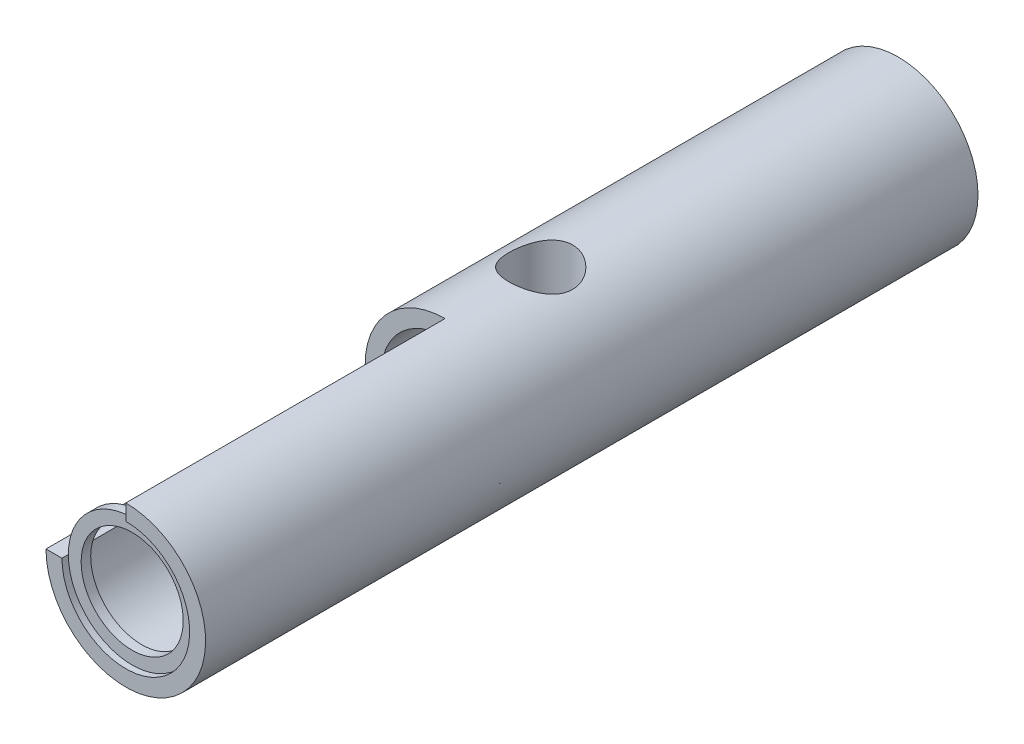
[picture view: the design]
ISO-10303-21;
HEADER;
FILE_DESCRIPTION(('STEP AP214'),'2;1');
FILE_NAME('part.step','',(''),(''),'','','');
FILE_SCHEMA(('AUTOMOTIVE_DESIGN { 1 0 10303 214 1 1 1 1 }'));
ENDSEC;
DATA;
#1=APPLICATION_CONTEXT('core data for automotive mechanical design processes');
#2=APPLICATION_PROTOCOL_DEFINITION('international standard','automotive_design',2000,#1);
#3=PRODUCT_CONTEXT('',#1,'mechanical');
#4=PRODUCT('Part','Part','',(#3));
#5=PRODUCT_RELATED_PRODUCT_CATEGORY('part','',(#4));
#6=PRODUCT_DEFINITION_FORMATION('','',#4);
#7=PRODUCT_DEFINITION_CONTEXT('part definition',#1,'design');
#8=PRODUCT_DEFINITION('design','',#6,#7);
#9=PRODUCT_DEFINITION_SHAPE('','',#8);
#10=(LENGTH_UNIT() NAMED_UNIT(*) SI_UNIT(.MILLI.,.METRE.));
#11=(NAMED_UNIT(*) PLANE_ANGLE_UNIT() SI_UNIT($,.RADIAN.));
#12=(NAMED_UNIT(*) SI_UNIT($,.STERADIAN.) SOLID_ANGLE_UNIT());
#13=UNCERTAINTY_MEASURE_WITH_UNIT(LENGTH_MEASURE(1.E-05),#10,'distance_accuracy_value','');
#14=(GEOMETRIC_REPRESENTATION_CONTEXT(3) GLOBAL_UNCERTAINTY_ASSIGNED_CONTEXT((#13)) GLOBAL_UNIT_ASSIGNED_CONTEXT((#10,
#11,#12)) REPRESENTATION_CONTEXT('',''));
#15=CARTESIAN_POINT('',(0.,0.,0.));
#16=DIRECTION('',(0.,0.,1.));
#17=DIRECTION('',(1.,0.,0.));
#18=AXIS2_PLACEMENT_3D('',#15,#16,#17);
#19=CARTESIAN_POINT('',(0.,0.,63.));
#20=DIRECTION('',(0.,0.,1.));
#21=DIRECTION('',(1.,0.,0.));
#22=AXIS2_PLACEMENT_3D('',#19,#20,#21);
#23=CYLINDRICAL_SURFACE('',#22,10.);
#24=DIRECTION('',(0.,0.,1.));
#25=VECTOR('',#24,1.);
#26=CARTESIAN_POINT('',(0.,10.,63.));
#27=LINE('',#26,#25);
#28=CARTESIAN_POINT('',(0.,10.,121.));
#29=VERTEX_POINT('',#28);
#30=CARTESIAN_POINT('',(0.,10.,120.));
#31=VERTEX_POINT('',#30);
#32=EDGE_CURVE('E107',#29,#31,#27,.F.);
#33=ORIENTED_EDGE('',*,*,#32,.T.);
#34=CARTESIAN_POINT('',(0.,0.,120.));
#35=DIRECTION('',(0.,0.,-1.));
#36=DIRECTION('',(-1.,0.,0.));
#37=AXIS2_PLACEMENT_3D('',#34,#35,#36);
#38=CIRCLE('',#37,10.);
#39=CARTESIAN_POINT('',(-10.,0.,120.));
#40=VERTEX_POINT('',#39);
#41=EDGE_CURVE('E106',#31,#40,#38,.T.);
#42=ORIENTED_EDGE('',*,*,#41,.T.);
#43=DIRECTION('',(0.,0.,1.));
#44=VECTOR('',#43,1.);
#45=CARTESIAN_POINT('',(-10.,0.,63.));
#46=LINE('',#45,#44);
#47=CARTESIAN_POINT('',(-10.,0.,121.));
#48=VERTEX_POINT('',#47);
#49=EDGE_CURVE('E51',#40,#48,#46,.T.);
#50=ORIENTED_EDGE('',*,*,#49,.T.);
#51=CARTESIAN_POINT('',(0.,0.,121.));
#52=DIRECTION('',(0.,0.,1.));
#53=DIRECTION('',(1.,0.,0.));
#54=AXIS2_PLACEMENT_3D('',#51,#52,#53);
#55=CIRCLE('',#54,10.);
#56=EDGE_CURVE('E212',#48,#29,#55,.T.);
#57=ORIENTED_EDGE('',*,*,#56,.T.);
#58=EDGE_LOOP('',(#33,#42,#50,#57));
#59=FACE_BOUND('',#58,.T.);
#60=ADVANCED_FACE('F41',(#59),#23,.F.);
#61=CARTESIAN_POINT('',(0.,0.,0.));
#62=DIRECTION('',(0.,0.,1.));
#63=DIRECTION('',(1.,0.,0.));
#64=AXIS2_PLACEMENT_3D('',#61,#62,#63);
#65=CYLINDRICAL_SURFACE('',#64,4.);
#66=CARTESIAN_POINT('',(4.,0.,53.));
#67=CARTESIAN_POINT('',(3.99999906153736,0.0751127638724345,52.9999978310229));
#68=CARTESIAN_POINT('',(3.9978772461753,0.150254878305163,52.9971622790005));
#69=CARTESIAN_POINT('',(3.9894472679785,0.2999085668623,52.9859741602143));
#70=CARTESIAN_POINT('',(3.98313625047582,0.374419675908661,52.9776178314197));
#71=CARTESIAN_POINT('',(3.95807727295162,0.596479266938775,52.9447707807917));
#72=CARTESIAN_POINT('',(3.93320424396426,0.742244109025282,52.9125044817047));
#73=CARTESIAN_POINT('',(3.85777127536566,1.0752679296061,52.8184478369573));
#74=CARTESIAN_POINT('',(3.80127986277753,1.25928076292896,52.7502867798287));
#75=CARTESIAN_POINT('',(3.66572012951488,1.61194054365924,52.5981035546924));
#76=CARTESIAN_POINT('',(3.58658817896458,1.78054239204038,52.5140369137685));
#77=CARTESIAN_POINT('',(3.43637278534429,2.05110258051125,52.3670054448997));
#78=CARTESIAN_POINT('',(3.37076459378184,2.15717257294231,52.305856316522));
#79=CARTESIAN_POINT('',(3.23028207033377,2.3623609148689,52.1824073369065));
#80=CARTESIAN_POINT('',(3.15540441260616,2.4614767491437,52.1201070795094));
#81=CARTESIAN_POINT('',(2.99663184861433,2.6524698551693,51.9962104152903));
#82=CARTESIAN_POINT('',(2.91274636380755,2.74435451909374,51.9346133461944));
#83=CARTESIAN_POINT('',(2.73598294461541,2.92061301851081,51.8136076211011));
#84=CARTESIAN_POINT('',(2.64310382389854,3.00498586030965,51.7541992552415));
#85=CARTESIAN_POINT('',(2.38958702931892,3.21416413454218,51.6042350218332));
#86=CARTESIAN_POINT('',(2.22188522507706,3.33264039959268,51.5165192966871));
#87=CARTESIAN_POINT('',(1.86487183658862,3.54474406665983,51.3566840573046));
#88=CARTESIAN_POINT('',(1.67559449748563,3.63841008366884,51.2845403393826));
#89=CARTESIAN_POINT('',(1.31063780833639,3.7834234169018,51.1716897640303));
#90=CARTESIAN_POINT('',(1.13770814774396,3.83916445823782,51.1277859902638));
#91=CARTESIAN_POINT('',(0.782375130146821,3.92699806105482,51.0582810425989));
#92=CARTESIAN_POINT('',(0.599977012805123,3.95910355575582,51.032669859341));
#93=CARTESIAN_POINT('',(0.230096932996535,3.99771600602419,51.0018408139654));
#94=CARTESIAN_POINT('',(0.042599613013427,4.00413433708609,50.9966935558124));
#95=CARTESIAN_POINT('',(-0.33083280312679,3.99067157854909,51.0074612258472));
#96=CARTESIAN_POINT('',(-0.516767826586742,3.97078927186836,51.0233771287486));
#97=CARTESIAN_POINT('',(-0.871367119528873,3.90786401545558,51.0734326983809));
#98=CARTESIAN_POINT('',(-1.04042037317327,3.86614236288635,51.1065319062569));
#99=CARTESIAN_POINT('',(-1.36834372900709,3.76260953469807,51.1879101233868));
#100=CARTESIAN_POINT('',(-1.5272112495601,3.70079328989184,51.2361929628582));
#101=CARTESIAN_POINT('',(-1.84705463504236,3.55279860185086,51.3502755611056));
#102=CARTESIAN_POINT('',(-2.00675938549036,3.46484696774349,51.417314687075));
#103=CARTESIAN_POINT('',(-2.30941782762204,3.27092428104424,51.5621191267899));
#104=CARTESIAN_POINT('',(-2.4523620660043,3.16494314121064,51.6398904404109));
#105=CARTESIAN_POINT('',(-2.7485304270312,2.91387626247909,51.81892978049));
#106=CARTESIAN_POINT('',(-2.89780217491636,2.76523277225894,51.9217371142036));
#107=CARTESIAN_POINT('',(-3.17076769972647,2.44748819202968,52.1301524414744));
#108=CARTESIAN_POINT('',(-3.29442988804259,2.27836224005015,52.2357637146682));
#109=CARTESIAN_POINT('',(-3.50457057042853,1.9375596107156,52.4311736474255));
#110=CARTESIAN_POINT('',(-3.59348348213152,1.76769812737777,52.5215155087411));
#111=CARTESIAN_POINT('',(-3.74778213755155,1.41126705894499,52.688357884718));
#112=CARTESIAN_POINT('',(-3.81321930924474,1.22473512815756,52.7648884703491));
#113=CARTESIAN_POINT('',(-3.90124400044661,0.894416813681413,52.8721238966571));
#114=CARTESIAN_POINT('',(-3.93080589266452,0.754774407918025,52.9096879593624));
#115=CARTESIAN_POINT('',(-3.97493954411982,0.469639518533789,52.9666539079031));
#116=CARTESIAN_POINT('',(-3.98954472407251,0.324160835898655,52.9860962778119));
#117=CARTESIAN_POINT('',(-4.00259995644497,0.0302735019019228,53.0034441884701));
#118=CARTESIAN_POINT('',(-4.00095637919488,-0.118147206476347,53.0012249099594));
#119=CARTESIAN_POINT('',(-3.98145195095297,-0.41209561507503,52.9753908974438));
#120=CARTESIAN_POINT('',(-3.96356821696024,-0.557618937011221,52.9517459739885));
#121=CARTESIAN_POINT('',(-3.90662980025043,-0.87812188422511,52.8789697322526));
#122=CARTESIAN_POINT('',(-3.86334682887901,-1.05117767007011,52.8248851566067));
#123=CARTESIAN_POINT('',(-3.7568227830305,-1.38460065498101,52.6995442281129));
#124=CARTESIAN_POINT('',(-3.69352220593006,-1.54492821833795,52.6282368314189));
#125=CARTESIAN_POINT('',(-3.56873529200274,-1.81092552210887,52.4971442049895));
#126=CARTESIAN_POINT('',(-3.5113936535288,-1.91964530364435,52.4394629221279));
#127=CARTESIAN_POINT('',(-3.38766369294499,-2.13041737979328,52.3215449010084));
#128=CARTESIAN_POINT('',(-3.32127165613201,-2.23246691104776,52.2613071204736));
#129=CARTESIAN_POINT('',(-3.17963685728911,-2.42995611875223,52.140127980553));
#130=CARTESIAN_POINT('',(-3.10438543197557,-2.52538917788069,52.0791859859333));
#131=CARTESIAN_POINT('',(-2.9452042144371,-2.70934721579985,51.9582475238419));
#132=CARTESIAN_POINT('',(-2.86127578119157,-2.79787327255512,51.8982509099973));
#133=CARTESIAN_POINT('',(-2.68353213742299,-2.96885093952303,51.779783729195));
#134=CARTESIAN_POINT('',(-2.5895923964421,-3.05119722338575,51.7213473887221));
#135=CARTESIAN_POINT('',(-2.39294409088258,-3.2077427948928,51.6083394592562));
#136=CARTESIAN_POINT('',(-2.29023415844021,-3.28194080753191,51.5537684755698));
#137=CARTESIAN_POINT('',(-2.07659269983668,-3.42110502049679,51.4500754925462));
#138=CARTESIAN_POINT('',(-1.96568453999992,-3.48609602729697,51.4009389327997));
#139=CARTESIAN_POINT('',(-1.73599312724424,-3.6059828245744,51.3094118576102));
#140=CARTESIAN_POINT('',(-1.61721438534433,-3.66088433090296,51.2670175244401));
#141=CARTESIAN_POINT('',(-1.32913962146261,-3.77693416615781,51.1767794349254));
#142=CARTESIAN_POINT('',(-1.15683679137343,-3.83342216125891,51.1323129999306));
#143=CARTESIAN_POINT('',(-0.802710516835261,-3.92287685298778,51.0615575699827));
#144=CARTESIAN_POINT('',(-0.620894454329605,-3.95586150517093,51.0352546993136));
#145=CARTESIAN_POINT('',(-0.251928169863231,-3.99638225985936,51.0029090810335));
#146=CARTESIAN_POINT('',(-0.0647609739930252,-4.00382550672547,50.9969402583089));
#147=CARTESIAN_POINT('',(0.308260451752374,-3.99246788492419,51.0060247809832));
#148=CARTESIAN_POINT('',(0.494114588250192,-3.97366516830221,51.0210796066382));
#149=CARTESIAN_POINT('',(0.848969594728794,-3.91279269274,51.0695200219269));
#150=CARTESIAN_POINT('',(1.01834018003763,-3.87202131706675,51.1018819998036));
#151=CARTESIAN_POINT('',(1.34704122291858,-3.7702931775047,51.1818959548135));
#152=CARTESIAN_POINT('',(1.50636906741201,-3.70933118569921,51.2295518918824));
#153=CARTESIAN_POINT('',(1.82676698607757,-3.56325105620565,51.3422757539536));
#154=CARTESIAN_POINT('',(1.98661951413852,-3.47641294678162,51.4085512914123));
#155=CARTESIAN_POINT('',(2.28972858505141,-3.2847146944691,51.5519328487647));
#156=CARTESIAN_POINT('',(2.43297624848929,-3.17984498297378,51.6290446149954));
#157=CARTESIAN_POINT('',(2.72976152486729,-2.931410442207,51.8066594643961));
#158=CARTESIAN_POINT('',(2.87940400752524,-2.78431890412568,51.9087197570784));
#159=CARTESIAN_POINT('',(3.15339914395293,-2.46975440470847,52.1159880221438));
#160=CARTESIAN_POINT('',(3.2777199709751,-2.30225621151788,52.2211997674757));
#161=CARTESIAN_POINT('',(3.43993958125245,-2.0435346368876,52.3707201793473));
#162=CARTESIAN_POINT('',(3.488247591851,-1.95998002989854,52.4172293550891));
#163=CARTESIAN_POINT('',(3.57912761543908,-1.78864740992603,52.5080121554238));
#164=CARTESIAN_POINT('',(3.62169886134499,-1.70086883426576,52.5522854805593));
#165=CARTESIAN_POINT('',(3.74029659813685,-1.43132131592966,52.6798301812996));
#166=CARTESIAN_POINT('',(3.80747088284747,-1.24292483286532,52.7580790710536));
#167=CARTESIAN_POINT('',(3.89828691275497,-0.907661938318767,52.8683954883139));
#168=CARTESIAN_POINT('',(3.92892882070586,-0.765010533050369,52.9072768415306));
#169=CARTESIAN_POINT('',(3.96316402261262,-0.546591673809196,52.9514490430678));
#170=CARTESIAN_POINT('',(3.97261660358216,-0.473140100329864,52.9638081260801));
#171=CARTESIAN_POINT('',(3.98745340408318,-0.325161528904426,52.983317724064));
#172=CARTESIAN_POINT('',(3.99284047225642,-0.250635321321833,52.9904718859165));
#173=CARTESIAN_POINT('',(3.99741959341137,-0.146618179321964,52.996562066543));
#174=CARTESIAN_POINT('',(3.99838660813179,-0.11732119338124,52.9978498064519));
#175=CARTESIAN_POINT('',(3.99967703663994,-0.058684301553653,52.9995692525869));
#176=CARTESIAN_POINT('',(4.00000036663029,-0.0293443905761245,53.0000008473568));
#177=CARTESIAN_POINT('',(4.,0.,53.));
#178=B_SPLINE_CURVE_WITH_KNOTS('',3,(#66,#67,#68,#69,#70,#71,#72,#73,#74,#75,#76,#77,#78,#79,
#80,#81,#82,#83,#84,#85,#86,#87,#88,#89,#90,#91,#92,#93,#94,#95,#96,#97,#98,#99,#100,#101,#102,
#103,#104,#105,#106,#107,#108,#109,#110,#111,#112,#113,#114,#115,#116,#117,#118,#119,#120,#121,
#122,#123,#124,#125,#126,#127,#128,#129,#130,#131,#132,#133,#134,#135,#136,#137,#138,#139,#140,
#141,#142,#143,#144,#145,#146,#147,#148,#149,#150,#151,#152,#153,#154,#155,#156,#157,#158,#159,
#160,#161,#162,#163,#164,#165,#166,#167,#168,#169,#170,#171,#172,#173,#174,#175,#176,#177),
.UNSPECIFIED.,.T.,.F.,(4,2,2,2,2,2,2,2,2,2,2,2,2,2,2,2,2,2,2,2,2,2,2,2,2,2,2,2,2,2,2,2,2,2,2,2,
2,2,2,2,2,2,2,2,2,2,2,2,2,2,2,2,2,2,2,4),(0.,0.225303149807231,0.450759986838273,
0.902589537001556,1.51190711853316,2.12295426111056,2.53921883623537,2.95563320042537,
3.37161619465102,3.78765413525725,4.45477512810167,5.12085162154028,5.67923095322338,
6.23730451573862,6.79730186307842,7.35732512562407,7.88682741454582,8.41646338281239,
8.99711927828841,9.57810111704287,10.2788135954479,10.9803852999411,11.6143729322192,
12.2469630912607,12.6881435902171,13.1283361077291,13.5710666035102,14.0144218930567,
14.5705602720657,15.1283675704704,15.5352238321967,15.942247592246,16.3496727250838,
16.7570341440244,17.1702378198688,17.5835060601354,17.9956387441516,18.4075372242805,
18.9651425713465,19.5223214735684,20.0815238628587,20.6407656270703,21.1700928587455,
21.6995572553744,22.2782911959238,22.8573331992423,23.5548944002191,24.2533270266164,
24.5745079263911,24.8957317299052,25.5365329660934,25.9876445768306,26.2126360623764,
26.4374697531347,26.5254777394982,26.6134971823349),.UNSPECIFIED.);
#179=CARTESIAN_POINT('',(4.,0.,53.));
#180=VERTEX_POINT('',#179);
#181=EDGE_CURVE('E182',#180,#180,#178,.T.);
#182=ORIENTED_EDGE('',*,*,#181,.T.);
#183=EDGE_LOOP('',(#182));
#184=FACE_BOUND('',#183,.T.);
#185=CARTESIAN_POINT('',(0.,0.,0.));
#186=DIRECTION('',(0.,0.,1.));
#187=DIRECTION('',(1.,0.,0.));
#188=AXIS2_PLACEMENT_3D('',#185,#186,#187);
#189=CIRCLE('',#188,4.);
#190=CARTESIAN_POINT('',(4.,0.,0.));
#191=VERTEX_POINT('',#190);
#192=EDGE_CURVE('E215',#191,#191,#189,.T.);
#193=ORIENTED_EDGE('',*,*,#192,.F.);
#194=EDGE_LOOP('',(#193));
#195=FACE_BOUND('',#194,.T.);
#196=ADVANCED_FACE('F230',(#184,#195),#65,.F.);
#197=CARTESIAN_POINT('',(0.,0.,121.));
#198=DIRECTION('',(0.,0.,-1.));
#199=DIRECTION('',(-1.,0.,0.));
#200=AXIS2_PLACEMENT_3D('',#197,#198,#199);
#201=CYLINDRICAL_SURFACE('',#200,12.5);
#202=CARTESIAN_POINT('',(0.,-12.5,59.));
#203=CARTESIAN_POINT('',(0.165963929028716,-12.4999970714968,58.9999949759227));
#204=CARTESIAN_POINT('',(0.331985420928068,-12.4966615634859,58.9861815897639));
#205=CARTESIAN_POINT('',(0.65928429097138,-12.4836783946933,58.9313672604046));
#206=CARTESIAN_POINT('',(0.820558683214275,-12.4740268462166,58.8903495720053));
#207=CARTESIAN_POINT('',(1.13358839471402,-12.4494823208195,58.7825076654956));
#208=CARTESIAN_POINT('',(1.28535442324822,-12.4345953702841,58.7157131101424));
#209=CARTESIAN_POINT('',(1.57552517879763,-12.4011725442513,58.5583145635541));
#210=CARTESIAN_POINT('',(1.71392971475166,-12.3826366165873,58.4677102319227));
#211=CARTESIAN_POINT('',(1.97609263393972,-12.3435386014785,58.2634358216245));
#212=CARTESIAN_POINT('',(2.0995595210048,-12.3229472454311,58.1493972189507));
#213=CARTESIAN_POINT('',(2.32581080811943,-12.2822574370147,57.9022811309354));
#214=CARTESIAN_POINT('',(2.42859304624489,-12.2621590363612,57.7692016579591));
#215=CARTESIAN_POINT('',(2.61189993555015,-12.224437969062,57.4855541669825));
#216=CARTESIAN_POINT('',(2.69210377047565,-12.2068525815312,57.3347734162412));
#217=CARTESIAN_POINT('',(2.82591582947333,-12.1765733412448,57.0213801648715));
#218=CARTESIAN_POINT('',(2.87952794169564,-12.1638787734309,56.8587693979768));
#219=CARTESIAN_POINT('',(2.95765058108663,-12.1451184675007,56.5295234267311));
#220=CARTESIAN_POINT('',(2.98268262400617,-12.1389341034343,56.3630188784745));
#221=CARTESIAN_POINT('',(3.00455808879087,-12.1335389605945,56.0280676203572));
#222=CARTESIAN_POINT('',(3.00140571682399,-12.1343271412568,55.8596212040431));
#223=CARTESIAN_POINT('',(2.96741912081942,-12.1426811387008,55.5295240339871));
#224=CARTESIAN_POINT('',(2.93720103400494,-12.1500960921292,55.3678054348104));
#225=CARTESIAN_POINT('',(2.85092141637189,-12.1706283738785,55.0518026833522));
#226=CARTESIAN_POINT('',(2.79485817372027,-12.1837460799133,54.8975190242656));
#227=CARTESIAN_POINT('',(2.65794121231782,-12.2143476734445,54.5990870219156));
#228=CARTESIAN_POINT('',(2.5768594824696,-12.2318714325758,54.4550475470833));
#229=CARTESIAN_POINT('',(2.39236688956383,-12.2692875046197,54.1823954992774));
#230=CARTESIAN_POINT('',(2.28895240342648,-12.2891802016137,54.0537854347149));
#231=CARTESIAN_POINT('',(2.05951493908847,-12.329732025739,53.8121064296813));
#232=CARTESIAN_POINT('',(1.93297064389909,-12.3503975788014,53.6995329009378));
#233=CARTESIAN_POINT('',(1.66255592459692,-12.3896951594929,53.4971152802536));
#234=CARTESIAN_POINT('',(1.51868504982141,-12.4083271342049,53.4072717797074));
#235=CARTESIAN_POINT('',(1.21702847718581,-12.4415394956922,53.2527027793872));
#236=CARTESIAN_POINT('',(1.05920278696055,-12.4561077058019,53.1880525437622));
#237=CARTESIAN_POINT('',(0.734497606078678,-12.4794620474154,53.0863349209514));
#238=CARTESIAN_POINT('',(0.567619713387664,-12.4882491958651,53.0492626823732));
#239=CARTESIAN_POINT('',(0.233787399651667,-12.4989027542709,53.004497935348));
#240=CARTESIAN_POINT('',(0.0669284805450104,-12.5009282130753,52.9961301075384));
#241=CARTESIAN_POINT('',(-0.265804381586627,-12.4982807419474,53.0071667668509));
#242=CARTESIAN_POINT('',(-0.431678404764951,-12.4936083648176,53.0265689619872));
#243=CARTESIAN_POINT('',(-0.755422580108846,-12.4781916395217,53.0920369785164));
#244=CARTESIAN_POINT('',(-0.913370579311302,-12.4675301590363,53.1377391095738));
#245=CARTESIAN_POINT('',(-1.21935330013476,-12.4413335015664,53.2540981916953));
#246=CARTESIAN_POINT('',(-1.3673870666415,-12.4257978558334,53.3247575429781));
#247=CARTESIAN_POINT('',(-1.6520615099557,-12.3911910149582,53.4903665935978));
#248=CARTESIAN_POINT('',(-1.78847176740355,-12.3720653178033,53.5857007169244));
#249=CARTESIAN_POINT('',(-2.04359904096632,-12.3324936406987,53.7974569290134));
#250=CARTESIAN_POINT('',(-2.16231325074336,-12.3120474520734,53.9138823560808));
#251=CARTESIAN_POINT('',(-2.38142453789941,-12.2715742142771,54.1676408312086));
#252=CARTESIAN_POINT('',(-2.4813497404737,-12.2515669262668,54.3053851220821));
#253=CARTESIAN_POINT('',(-2.65666020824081,-12.2147538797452,54.5960904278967));
#254=CARTESIAN_POINT('',(-2.7320465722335,-12.1979479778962,54.7490507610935));
#255=CARTESIAN_POINT('',(-2.85558993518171,-12.1696189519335,55.065012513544));
#256=CARTESIAN_POINT('',(-2.90390754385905,-12.1580647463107,55.2279482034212));
#257=CARTESIAN_POINT('',(-2.97238380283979,-12.1415072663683,55.5599461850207));
#258=CARTESIAN_POINT('',(-2.99254804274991,-12.1365026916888,55.7290072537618));
#259=CARTESIAN_POINT('',(-3.00387066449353,-12.1337046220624,56.0636707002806));
#260=CARTESIAN_POINT('',(-2.99578106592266,-12.1357241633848,56.2292464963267));
#261=CARTESIAN_POINT('',(-2.95253345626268,-12.1463176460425,56.5565997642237));
#262=CARTESIAN_POINT('',(-2.91737590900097,-12.1548914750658,56.7183773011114));
#263=CARTESIAN_POINT('',(-2.82138591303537,-12.1775274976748,57.0327975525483));
#264=CARTESIAN_POINT('',(-2.76068402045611,-12.191561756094,57.1854822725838));
#265=CARTESIAN_POINT('',(-2.61543373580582,-12.2235433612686,57.4786044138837));
#266=CARTESIAN_POINT('',(-2.53088229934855,-12.2414912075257,57.6190402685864));
#267=CARTESIAN_POINT('',(-2.33793007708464,-12.279819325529,57.8873370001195));
#268=CARTESIAN_POINT('',(-2.22900267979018,-12.3002478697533,58.0148123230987));
#269=CARTESIAN_POINT('',(-1.99143074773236,-12.3409359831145,58.2499199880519));
#270=CARTESIAN_POINT('',(-1.86278158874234,-12.361195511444,58.3575476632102));
#271=CARTESIAN_POINT('',(-1.5868829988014,-12.3996570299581,58.5516092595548));
#272=CARTESIAN_POINT('',(-1.43936414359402,-12.4178200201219,58.637668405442));
#273=CARTESIAN_POINT('',(-1.13153622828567,-12.4496380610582,58.7836295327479));
#274=CARTESIAN_POINT('',(-0.971236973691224,-12.4632965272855,58.8435513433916));
#275=CARTESIAN_POINT('',(-0.675887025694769,-12.4824059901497,58.9260386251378));
#276=CARTESIAN_POINT('',(-0.542312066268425,-12.4889599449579,58.9537166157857));
#277=CARTESIAN_POINT('',(-0.272504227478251,-12.4977580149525,58.9906987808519));
#278=CARTESIAN_POINT('',(-0.136271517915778,-12.5000024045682,59.0000041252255));
#279=CARTESIAN_POINT('',(0.,-12.5,59.));
#280=B_SPLINE_CURVE_WITH_KNOTS('',3,(#202,#203,#204,#205,#206,#207,#208,#209,#210,#211,#212,
#213,#214,#215,#216,#217,#218,#219,#220,#221,#222,#223,#224,#225,#226,#227,#228,#229,#230,#231,
#232,#233,#234,#235,#236,#237,#238,#239,#240,#241,#242,#243,#244,#245,#246,#247,#248,#249,#250,
#251,#252,#253,#254,#255,#256,#257,#258,#259,#260,#261,#262,#263,#264,#265,#266,#267,#268,#269,
#270,#271,#272,#273,#274,#275,#276,#277,#278,#279),.UNSPECIFIED.,.T.,.F.,(4,2,2,2,2,2,2,2,2,2,2,
2,2,2,2,2,2,2,2,2,2,2,2,2,2,2,2,2,2,2,2,2,2,2,2,2,2,2,4),(0.,0.497392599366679,
0.995091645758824,1.49221966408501,1.98935478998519,2.49500570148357,3.00070943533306,
3.51327262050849,4.02576083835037,4.52873995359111,5.03164400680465,5.52338274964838,
6.01515406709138,6.51154667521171,7.00801987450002,7.51749958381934,8.0269925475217,
8.53799614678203,9.04890983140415,9.54771776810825,10.0464845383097,10.5385143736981,
11.0305915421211,11.5308523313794,12.031192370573,12.5427824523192,13.0543496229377,
13.5628484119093,14.0712462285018,14.5662165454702,15.0611783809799,15.5536406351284,
16.0461657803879,16.5505844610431,17.0551215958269,17.5678974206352,18.0802835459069,
18.4887142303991,18.897118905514),.UNSPECIFIED.);
#281=CARTESIAN_POINT('',(0.,-12.5,59.));
#282=VERTEX_POINT('',#281);
#283=EDGE_CURVE('E146',#282,#282,#280,.T.);
#284=ORIENTED_EDGE('',*,*,#283,.T.);
#285=EDGE_LOOP('',(#284));
#286=FACE_BOUND('',#285,.T.);
#287=CARTESIAN_POINT('',(0.,12.5,61.));
#288=CARTESIAN_POINT('',(-0.134428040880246,12.4999993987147,60.9999992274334));
#289=CARTESIAN_POINT('',(-0.268907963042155,12.4978254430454,60.9945712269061));
#290=CARTESIAN_POINT('',(-0.53691632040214,12.4891841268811,60.972908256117));
#291=CARTESIAN_POINT('',(-0.670444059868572,12.482713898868,60.9566660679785));
#292=CARTESIAN_POINT('',(-0.935792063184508,12.4656328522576,60.9134912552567));
#293=CARTESIAN_POINT('',(-1.06760803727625,12.45501315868,60.8865357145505));
#294=CARTESIAN_POINT('',(-1.32834211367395,12.4299104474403,60.822193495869));
#295=CARTESIAN_POINT('',(-1.45725900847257,12.4154258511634,60.7848025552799));
#296=CARTESIAN_POINT('',(-1.71081101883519,12.3830283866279,60.7000976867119));
#297=CARTESIAN_POINT('',(-1.83546024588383,12.3651284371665,60.6528210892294));
#298=CARTESIAN_POINT('',(-2.08021423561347,12.3263173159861,60.5486729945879));
#299=CARTESIAN_POINT('',(-2.20031728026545,12.3054050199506,60.4917979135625));
#300=CARTESIAN_POINT('',(-2.55253650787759,12.2389309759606,60.3075069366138));
#301=CARTESIAN_POINT('',(-2.77691477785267,12.1895849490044,60.1663067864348));
#302=CARTESIAN_POINT('',(-3.20878788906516,12.0832695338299,59.8444050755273));
#303=CARTESIAN_POINT('',(-3.41514420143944,12.0260638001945,59.6622677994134));
#304=CARTESIAN_POINT('',(-3.795448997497,11.9115080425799,59.2664655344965));
#305=CARTESIAN_POINT('',(-3.96938162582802,11.8541579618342,59.0527852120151));
#306=CARTESIAN_POINT('',(-4.20603567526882,11.7714356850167,58.7073939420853));
#307=CARTESIAN_POINT('',(-4.28222203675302,11.7438622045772,58.5852200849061));
#308=CARTESIAN_POINT('',(-4.42396507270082,11.6912035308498,58.3343638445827));
#309=CARTESIAN_POINT('',(-4.48952611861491,11.6661173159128,58.2056841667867));
#310=CARTESIAN_POINT('',(-4.60945924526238,11.6192528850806,57.9426245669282));
#311=CARTESIAN_POINT('',(-4.66383056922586,11.5974748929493,57.8082442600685));
#312=CARTESIAN_POINT('',(-4.76082403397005,11.5579971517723,57.5347911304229));
#313=CARTESIAN_POINT('',(-4.80345206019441,11.5402953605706,57.39572069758));
#314=CARTESIAN_POINT('',(-4.87487504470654,11.5103008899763,57.1202338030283));
#315=CARTESIAN_POINT('',(-4.90420529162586,11.4978009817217,56.9839786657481));
#316=CARTESIAN_POINT('',(-4.95140857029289,11.4775526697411,56.709206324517));
#317=CARTESIAN_POINT('',(-4.9692867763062,11.4698021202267,56.5706901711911));
#318=CARTESIAN_POINT('',(-4.99338985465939,11.4593294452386,56.2924867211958));
#319=CARTESIAN_POINT('',(-4.99961718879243,11.4566062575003,56.152799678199));
#320=CARTESIAN_POINT('',(-5.00034850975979,11.4562871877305,55.8733924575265));
#321=CARTESIAN_POINT('',(-4.99485304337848,11.4586910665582,55.7336722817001));
#322=CARTESIAN_POINT('',(-4.97300139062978,11.4681900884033,55.4650957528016));
#323=CARTESIAN_POINT('',(-4.95743098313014,11.4749456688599,55.3361625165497));
#324=CARTESIAN_POINT('',(-4.91636669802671,11.4925992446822,55.0801331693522));
#325=CARTESIAN_POINT('',(-4.89086955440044,11.5034986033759,54.9530376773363));
#326=CARTESIAN_POINT('',(-4.83020381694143,11.5291029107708,54.7015982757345));
#327=CARTESIAN_POINT('',(-4.79503755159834,11.5438069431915,54.5772537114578));
#328=CARTESIAN_POINT('',(-4.71535272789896,11.5765839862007,54.332038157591));
#329=CARTESIAN_POINT('',(-4.67083057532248,11.5946582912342,54.2111685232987));
#330=CARTESIAN_POINT('',(-4.52178156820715,11.6539749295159,53.850100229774));
#331=CARTESIAN_POINT('',(-4.40296429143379,11.6997808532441,53.6163670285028));
#332=CARTESIAN_POINT('',(-4.13125151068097,11.7984565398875,53.1714203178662));
#333=CARTESIAN_POINT('',(-3.97834320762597,11.851328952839,52.9602153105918));
#334=CARTESIAN_POINT('',(-3.62889137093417,11.9631659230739,52.5489925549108));
#335=CARTESIAN_POINT('',(-3.42988845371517,12.0222854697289,52.3511017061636));
#336=CARTESIAN_POINT('',(-3.0007412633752,12.1365017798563,51.9907652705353));
#337=CARTESIAN_POINT('',(-2.77059080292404,12.1915977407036,51.8283267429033));
#338=CARTESIAN_POINT('',(-2.40397180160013,12.2673153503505,51.6134750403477));
#339=CARTESIAN_POINT('',(-2.27679500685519,12.2916102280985,51.5461273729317));
#340=CARTESIAN_POINT('',(-2.01664956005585,12.3369572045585,51.4224644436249));
#341=CARTESIAN_POINT('',(-1.88368330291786,12.3580106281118,51.3661446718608));
#342=CARTESIAN_POINT('',(-1.61291597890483,12.3962575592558,51.2650884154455));
#343=CARTESIAN_POINT('',(-1.47511586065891,12.4134518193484,51.2203496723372));
#344=CARTESIAN_POINT('',(-1.19570710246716,12.4434728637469,51.1429130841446));
#345=CARTESIAN_POINT('',(-1.05409872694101,12.4562999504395,51.1102144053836));
#346=CARTESIAN_POINT('',(-0.776729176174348,12.4765727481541,51.0588068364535));
#347=CARTESIAN_POINT('',(-0.641120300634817,12.4842928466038,51.0393823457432));
#348=CARTESIAN_POINT('',(-0.368536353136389,12.4953107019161,51.0117185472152));
#349=CARTESIAN_POINT('',(-0.231560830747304,12.4986069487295,51.0034830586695));
#350=CARTESIAN_POINT('',(0.0425534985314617,12.5006785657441,50.9983032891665));
#351=CARTESIAN_POINT('',(0.179692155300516,12.4994566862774,51.0013521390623));
#352=CARTESIAN_POINT('',(0.453193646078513,12.4925311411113,51.0186951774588));
#353=CARTESIAN_POINT('',(0.589556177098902,12.4868258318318,51.032993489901));
#354=CARTESIAN_POINT('',(0.854248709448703,12.4714486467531,51.0717821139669));
#355=CARTESIAN_POINT('',(0.982662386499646,12.4619685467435,51.095780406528));
#356=CARTESIAN_POINT('',(1.236951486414,12.4393027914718,51.1536650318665));
#357=CARTESIAN_POINT('',(1.36282600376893,12.4261158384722,51.1875548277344));
#358=CARTESIAN_POINT('',(1.61115102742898,12.396363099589,51.2649082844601));
#359=CARTESIAN_POINT('',(1.73360251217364,12.3797982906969,51.3083691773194));
#360=CARTESIAN_POINT('',(1.97439656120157,12.3436873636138,51.4045030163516));
#361=CARTESIAN_POINT('',(2.0927375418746,12.324140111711,51.4571794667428));
#362=CARTESIAN_POINT('',(2.44755555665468,12.2604306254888,51.6319072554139));
#363=CARTESIAN_POINT('',(2.67640599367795,12.2121249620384,51.7683460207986));
#364=CARTESIAN_POINT('',(3.10864805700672,12.1093295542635,52.0748684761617));
#365=CARTESIAN_POINT('',(3.31202942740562,12.0548373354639,52.2449656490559));
#366=CARTESIAN_POINT('',(3.70179180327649,11.941130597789,52.6271584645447));
#367=CARTESIAN_POINT('',(3.88616393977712,11.8818418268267,52.8412854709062));
#368=CARTESIAN_POINT('',(4.2168988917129,11.7685360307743,53.2986485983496));
#369=CARTESIAN_POINT('',(4.36325544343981,11.7145198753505,53.5418895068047));
#370=CARTESIAN_POINT('',(4.55142555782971,11.6421255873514,53.9251186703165));
#371=CARTESIAN_POINT('',(4.60914530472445,11.6193337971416,54.0566797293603));
#372=CARTESIAN_POINT('',(4.71320516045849,11.5775147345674,54.3247871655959));
#373=CARTESIAN_POINT('',(4.75955021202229,11.5584858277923,54.4613313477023));
#374=CARTESIAN_POINT('',(4.84036067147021,11.5248785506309,54.7383631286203));
#375=CARTESIAN_POINT('',(4.87483074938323,11.5102984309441,54.8788491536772));
#376=CARTESIAN_POINT('',(4.93151664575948,11.4861263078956,55.1626946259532));
#377=CARTESIAN_POINT('',(4.95373349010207,11.4765338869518,55.3060538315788));
#378=CARTESIAN_POINT('',(4.9844819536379,11.463210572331,55.5839989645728));
#379=CARTESIAN_POINT('',(4.9938856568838,11.4591065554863,55.7184712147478));
#380=CARTESIAN_POINT('',(5.00180093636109,11.4556539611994,55.9878460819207));
#381=CARTESIAN_POINT('',(5.00030885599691,11.4563069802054,56.1227488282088));
#382=CARTESIAN_POINT('',(4.98644346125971,11.4623486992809,56.3918171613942));
#383=CARTESIAN_POINT('',(4.97407559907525,11.4677350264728,56.5259830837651));
#384=CARTESIAN_POINT('',(4.93860056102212,11.4830569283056,56.7926720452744));
#385=CARTESIAN_POINT('',(4.91548933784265,11.4929942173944,56.9251944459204));
#386=CARTESIAN_POINT('',(4.85990688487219,11.5166044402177,57.182329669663));
#387=CARTESIAN_POINT('',(4.82784722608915,11.5301119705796,57.3070467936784));
#388=CARTESIAN_POINT('',(4.75435551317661,11.5606089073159,57.553266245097));
#389=CARTESIAN_POINT('',(4.71292020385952,11.5775995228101,57.6747674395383));
#390=CARTESIAN_POINT('',(4.57505004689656,11.6330901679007,58.0333144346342));
#391=CARTESIAN_POINT('',(4.46501084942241,11.6761269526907,58.2645872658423));
#392=CARTESIAN_POINT('',(4.20467910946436,11.7724663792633,58.7190564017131));
#393=CARTESIAN_POINT('',(4.05244254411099,11.8262157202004,58.9410320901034));
#394=CARTESIAN_POINT('',(3.71470108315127,11.9366014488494,59.3574978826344));
#395=CARTESIAN_POINT('',(3.52918616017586,11.9932387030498,59.5519796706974));
#396=CARTESIAN_POINT('',(3.22271513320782,12.0779292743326,59.8255134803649));
#397=CARTESIAN_POINT('',(3.11206947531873,12.1069791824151,59.9160564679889));
#398=CARTESIAN_POINT('',(2.88318647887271,12.1635153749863,60.0874993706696));
#399=CARTESIAN_POINT('',(2.76495189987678,12.1910022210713,60.1684027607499));
#400=CARTESIAN_POINT('',(2.52148785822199,12.2436771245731,60.3200337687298));
#401=CARTESIAN_POINT('',(2.39625194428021,12.268863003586,60.3907517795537));
#402=CARTESIAN_POINT('',(2.13974317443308,12.3161883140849,60.5213045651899));
#403=CARTESIAN_POINT('',(2.00847311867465,12.338329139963,60.5811443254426));
#404=CARTESIAN_POINT('',(1.7431850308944,12.378569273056,60.6884332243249));
#405=CARTESIAN_POINT('',(1.60925996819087,12.3967345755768,60.736087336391));
#406=CARTESIAN_POINT('',(1.33744351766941,12.4289968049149,60.819902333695));
#407=CARTESIAN_POINT('',(1.19955402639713,12.4430956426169,60.8560686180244));
#408=CARTESIAN_POINT('',(0.921178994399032,12.4667917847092,60.9164690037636));
#409=CARTESIAN_POINT('',(0.780700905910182,12.4764003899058,60.9407330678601));
#410=CARTESIAN_POINT('',(0.498015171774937,12.4908758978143,60.977174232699));
#411=CARTESIAN_POINT('',(0.355808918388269,12.4957463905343,60.9893604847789));
#412=CARTESIAN_POINT('',(0.177825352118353,12.4987857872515,60.9969636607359));
#413=CARTESIAN_POINT('',(0.142272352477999,12.4992409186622,60.9981020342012));
#414=CARTESIAN_POINT('',(0.0711474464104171,12.4998481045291,60.9996203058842));
#415=CARTESIAN_POINT('',(0.0355755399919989,12.5000001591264,61.0000002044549));
#416=CARTESIAN_POINT('',(0.,12.5,61.));
#417=B_SPLINE_CURVE_WITH_KNOTS('',3,(#287,#288,#289,#290,#291,#292,#293,#294,#295,#296,#297,
#298,#299,#300,#301,#302,#303,#304,#305,#306,#307,#308,#309,#310,#311,#312,#313,#314,#315,#316,
#317,#318,#319,#320,#321,#322,#323,#324,#325,#326,#327,#328,#329,#330,#331,#332,#333,#334,#335,
#336,#337,#338,#339,#340,#341,#342,#343,#344,#345,#346,#347,#348,#349,#350,#351,#352,#353,#354,
#355,#356,#357,#358,#359,#360,#361,#362,#363,#364,#365,#366,#367,#368,#369,#370,#371,#372,#373,
#374,#375,#376,#377,#378,#379,#380,#381,#382,#383,#384,#385,#386,#387,#388,#389,#390,#391,#392,
#393,#394,#395,#396,#397,#398,#399,#400,#401,#402,#403,#404,#405,#406,#407,#408,#409,#410,#411,
#412,#413,#414,#415,#416),.UNSPECIFIED.,.T.,.F.,(4,2,2,2,2,2,2,2,2,2,2,2,2,2,2,2,2,2,2,2,2,2,2,
2,2,2,2,2,2,2,2,2,2,2,2,2,2,2,2,2,2,2,2,2,2,2,2,2,2,2,2,2,2,2,2,2,2,2,2,2,2,2,2,2,4),(0.,
0.40324754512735,0.806764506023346,1.21114928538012,1.61569948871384,2.01874874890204,
2.42194883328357,3.22723902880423,4.06710473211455,4.90738006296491,5.34671991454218,
5.78587855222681,6.22506688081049,6.66403469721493,7.08328748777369,7.50235071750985,
7.92132539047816,8.34028052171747,8.72995920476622,9.11976620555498,9.50947941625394,
9.8993426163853,10.6941760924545,11.4893084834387,12.345906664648,13.2026752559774,
13.6400384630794,14.0772224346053,14.5143210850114,14.9513894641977,15.3624968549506,
15.7737445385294,16.1847419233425,16.5958900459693,16.9883780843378,17.3810037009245,
17.7735159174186,18.1661777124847,18.9747143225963,19.783575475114,20.6458383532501,
21.5082432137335,21.944151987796,22.379871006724,22.815418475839,23.2509294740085,
23.655003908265,24.0592139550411,24.4632214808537,24.8673813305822,25.2553678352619,
25.6434892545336,26.4191721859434,27.2392679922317,28.0596113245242,28.4968494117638,
28.9339293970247,29.3714189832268,29.8087075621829,30.2380680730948,30.667226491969,
31.0952989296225,31.5230467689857,31.6297637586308,31.7364806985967),.UNSPECIFIED.);
#418=CARTESIAN_POINT('',(0.,12.5,61.));
#419=VERTEX_POINT('',#418);
#420=EDGE_CURVE('E187',#419,#419,#417,.T.);
#421=ORIENTED_EDGE('',*,*,#420,.T.);
#422=EDGE_LOOP('',(#421));
#423=FACE_BOUND('',#422,.T.);
#424=CARTESIAN_POINT('',(0.,0.,121.));
#425=DIRECTION('',(0.,0.,1.));
#426=DIRECTION('',(1.,0.,0.));
#427=AXIS2_PLACEMENT_3D('',#424,#425,#426);
#428=CIRCLE('',#427,12.5);
#429=CARTESIAN_POINT('',(-12.5,0.,121.));
#430=VERTEX_POINT('',#429);
#431=CARTESIAN_POINT('',(0.,12.5,121.));
#432=VERTEX_POINT('',#431);
#433=EDGE_CURVE('E199',#430,#432,#428,.T.);
#434=ORIENTED_EDGE('',*,*,#433,.F.);
#435=DIRECTION('',(0.,0.,-1.));
#436=VECTOR('',#435,1.);
#437=CARTESIAN_POINT('',(-12.5,0.,71.));
#438=LINE('',#437,#436);
#439=CARTESIAN_POINT('',(-12.5,0.,71.));
#440=VERTEX_POINT('',#439);
#441=EDGE_CURVE('E124',#430,#440,#438,.T.);
#442=ORIENTED_EDGE('',*,*,#441,.T.);
#443=CARTESIAN_POINT('',(0.,0.,71.));
#444=DIRECTION('',(0.,0.,-1.));
#445=DIRECTION('',(0.,1.,0.));
#446=AXIS2_PLACEMENT_3D('',#443,#444,#445);
#447=CIRCLE('',#446,12.5);
#448=CARTESIAN_POINT('',(0.,12.5,71.));
#449=VERTEX_POINT('',#448);
#450=EDGE_CURVE('E140',#440,#449,#447,.T.);
#451=ORIENTED_EDGE('',*,*,#450,.T.);
#452=DIRECTION('',(0.,0.,-1.));
#453=VECTOR('',#452,1.);
#454=CARTESIAN_POINT('',(0.,12.5,121.));
#455=LINE('',#454,#453);
#456=EDGE_CURVE('E136',#449,#432,#455,.F.);
#457=ORIENTED_EDGE('',*,*,#456,.T.);
#458=EDGE_LOOP('',(#434,#442,#451,#457));
#459=FACE_BOUND('',#458,.T.);
#460=CARTESIAN_POINT('',(0.,0.,0.));
#461=DIRECTION('',(0.,0.,1.));
#462=DIRECTION('',(1.,0.,0.));
#463=AXIS2_PLACEMENT_3D('',#460,#461,#462);
#464=CIRCLE('',#463,12.5);
#465=CARTESIAN_POINT('',(12.5,0.,0.));
#466=VERTEX_POINT('',#465);
#467=EDGE_CURVE('E203',#466,#466,#464,.T.);
#468=ORIENTED_EDGE('',*,*,#467,.T.);
#469=EDGE_LOOP('',(#468));
#470=FACE_BOUND('',#469,.T.);
#471=ADVANCED_FACE('F43',(#286,#423,#459,#470),#201,.T.);
#472=CARTESIAN_POINT('',(0.,0.,121.));
#473=DIRECTION('',(0.,0.,1.));
#474=DIRECTION('',(1.,0.,0.));
#475=AXIS2_PLACEMENT_3D('',#472,#473,#474);
#476=PLANE('',#475);
#477=DIRECTION('',(1.,0.,0.));
#478=VECTOR('',#477,1.);
#479=CARTESIAN_POINT('',(0.,0.,121.));
#480=LINE('',#479,#478);
#481=EDGE_CURVE('E100',#430,#48,#480,.T.);
#482=ORIENTED_EDGE('',*,*,#481,.F.);
#483=ORIENTED_EDGE('',*,*,#433,.T.);
#484=DIRECTION('',(0.,1.,0.));
#485=VECTOR('',#484,1.);
#486=CARTESIAN_POINT('',(0.,0.,121.));
#487=LINE('',#486,#485);
#488=EDGE_CURVE('E133',#29,#432,#487,.T.);
#489=ORIENTED_EDGE('',*,*,#488,.F.);
#490=ORIENTED_EDGE('',*,*,#56,.F.);
#491=EDGE_LOOP('',(#482,#483,#489,#490));
#492=FACE_BOUND('',#491,.T.);
#493=ADVANCED_FACE('F229',(#492),#476,.T.);
#494=CARTESIAN_POINT('',(0.,0.,0.));
#495=DIRECTION('',(0.,0.,1.));
#496=DIRECTION('',(1.,0.,0.));
#497=AXIS2_PLACEMENT_3D('',#494,#495,#496);
#498=PLANE('',#497);
#499=ORIENTED_EDGE('',*,*,#192,.T.);
#500=EDGE_LOOP('',(#499));
#501=FACE_BOUND('',#500,.T.);
#502=ORIENTED_EDGE('',*,*,#467,.F.);
#503=EDGE_LOOP('',(#502));
#504=FACE_BOUND('',#503,.T.);
#505=ADVANCED_FACE('F236',(#501,#504),#498,.F.);
#506=CARTESIAN_POINT('',(0.,0.,63.));
#507=DIRECTION('',(0.,0.,1.));
#508=DIRECTION('',(1.,0.,0.));
#509=AXIS2_PLACEMENT_3D('',#506,#507,#508);
#510=CIRCLE('',#509,10.);
#511=CARTESIAN_POINT('',(10.,0.,63.));
#512=VERTEX_POINT('',#511);
#513=EDGE_CURVE('E210',#512,#512,#510,.T.);
#514=ORIENTED_EDGE('',*,*,#513,.F.);
#515=EDGE_LOOP('',(#514));
#516=FACE_BOUND('',#515,.T.);
#517=CARTESIAN_POINT('',(-10.,0.,71.));
#518=VERTEX_POINT('',#517);
#519=CARTESIAN_POINT('',(-10.,0.,118.5));
#520=VERTEX_POINT('',#519);
#521=EDGE_CURVE('E12',#518,#520,#46,.T.);
#522=ORIENTED_EDGE('',*,*,#521,.T.);
#523=CARTESIAN_POINT('',(0.,0.,118.5));
#524=DIRECTION('',(0.,0.,-1.));
#525=DIRECTION('',(-1.,0.,0.));
#526=AXIS2_PLACEMENT_3D('',#523,#524,#525);
#527=CIRCLE('',#526,10.);
#528=CARTESIAN_POINT('',(0.,10.,118.5));
#529=VERTEX_POINT('',#528);
#530=EDGE_CURVE('E57',#529,#520,#527,.T.);
#531=ORIENTED_EDGE('',*,*,#530,.F.);
#532=CARTESIAN_POINT('',(0.,10.,71.));
#533=VERTEX_POINT('',#532);
#534=EDGE_CURVE('E188',#529,#533,#27,.F.);
#535=ORIENTED_EDGE('',*,*,#534,.T.);
#536=CARTESIAN_POINT('',(0.,0.,71.));
#537=DIRECTION('',(0.,0.,-1.));
#538=DIRECTION('',(0.,1.,0.));
#539=AXIS2_PLACEMENT_3D('',#536,#537,#538);
#540=CIRCLE('',#539,10.);
#541=EDGE_CURVE('E104',#533,#518,#540,.F.);
#542=ORIENTED_EDGE('',*,*,#541,.T.);
#543=EDGE_LOOP('',(#522,#531,#535,#542));
#544=FACE_BOUND('',#543,.T.);
#545=ADVANCED_FACE('F191',(#516,#544),#23,.F.);
#546=CARTESIAN_POINT('',(0.,0.,63.));
#547=DIRECTION('',(0.,0.,1.));
#548=DIRECTION('',(1.,0.,0.));
#549=AXIS2_PLACEMENT_3D('',#546,#547,#548);
#550=PLANE('',#549);
#551=CARTESIAN_POINT('',(0.,0.,63.));
#552=DIRECTION('',(0.,0.,1.));
#553=DIRECTION('',(1.,0.,0.));
#554=AXIS2_PLACEMENT_3D('',#551,#552,#553);
#555=CIRCLE('',#554,4.);
#556=CARTESIAN_POINT('',(4.,0.,63.));
#557=VERTEX_POINT('',#556);
#558=EDGE_CURVE('E218',#557,#557,#555,.T.);
#559=ORIENTED_EDGE('',*,*,#558,.F.);
#560=EDGE_LOOP('',(#559));
#561=FACE_BOUND('',#560,.T.);
#562=ORIENTED_EDGE('',*,*,#513,.T.);
#563=EDGE_LOOP('',(#562));
#564=FACE_BOUND('',#563,.T.);
#565=ADVANCED_FACE('F244',(#561,#564),#550,.T.);
#566=CARTESIAN_POINT('',(4.,0.,59.));
#567=CARTESIAN_POINT('',(3.99999906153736,-0.0751127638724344,59.0000021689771));
#568=CARTESIAN_POINT('',(3.9978772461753,-0.150254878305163,59.0028377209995));
#569=CARTESIAN_POINT('',(3.9894472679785,-0.2999085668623,59.0140258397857));
#570=CARTESIAN_POINT('',(3.98313625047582,-0.374419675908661,59.0223821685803));
#571=CARTESIAN_POINT('',(3.95807727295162,-0.596479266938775,59.0552292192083));
#572=CARTESIAN_POINT('',(3.93320424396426,-0.742244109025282,59.0874955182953));
#573=CARTESIAN_POINT('',(3.85777127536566,-1.0752679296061,59.1815521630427));
#574=CARTESIAN_POINT('',(3.80127986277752,-1.25928076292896,59.2497132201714));
#575=CARTESIAN_POINT('',(3.66572012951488,-1.61194054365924,59.4018964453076));
#576=CARTESIAN_POINT('',(3.58658817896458,-1.78054239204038,59.4859630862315));
#577=CARTESIAN_POINT('',(3.43637278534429,-2.05110258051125,59.6329945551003));
#578=CARTESIAN_POINT('',(3.37076459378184,-2.15717257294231,59.694143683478));
#579=CARTESIAN_POINT('',(3.23028207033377,-2.3623609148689,59.8175926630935));
#580=CARTESIAN_POINT('',(3.15540441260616,-2.4614767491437,59.8798929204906));
#581=CARTESIAN_POINT('',(2.99663184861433,-2.6524698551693,60.0037895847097));
#582=CARTESIAN_POINT('',(2.91274636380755,-2.74435451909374,60.0653866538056));
#583=CARTESIAN_POINT('',(2.73598294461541,-2.92061301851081,60.1863923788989));
#584=CARTESIAN_POINT('',(2.64310382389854,-3.00498586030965,60.2458007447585));
#585=CARTESIAN_POINT('',(2.38958702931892,-3.21416413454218,60.3957649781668));
#586=CARTESIAN_POINT('',(2.22188522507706,-3.33264039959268,60.4834807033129));
#587=CARTESIAN_POINT('',(1.86487183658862,-3.54474406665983,60.6433159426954));
#588=CARTESIAN_POINT('',(1.67559449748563,-3.63841008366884,60.7154596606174));
#589=CARTESIAN_POINT('',(1.31063780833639,-3.7834234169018,60.8283102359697));
#590=CARTESIAN_POINT('',(1.13770814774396,-3.83916445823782,60.8722140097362));
#591=CARTESIAN_POINT('',(0.782375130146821,-3.92699806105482,60.9417189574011));
#592=CARTESIAN_POINT('',(0.599977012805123,-3.95910355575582,60.967330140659));
#593=CARTESIAN_POINT('',(0.230096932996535,-3.99771600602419,60.9981591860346));
#594=CARTESIAN_POINT('',(0.042599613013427,-4.00413433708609,61.0033064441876));
#595=CARTESIAN_POINT('',(-0.33083280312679,-3.99067157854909,60.9925387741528));
#596=CARTESIAN_POINT('',(-0.516767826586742,-3.97078927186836,60.9766228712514));
#597=CARTESIAN_POINT('',(-0.871367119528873,-3.90786401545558,60.9265673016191));
#598=CARTESIAN_POINT('',(-1.04042037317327,-3.86614236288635,60.8934680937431));
#599=CARTESIAN_POINT('',(-1.36834372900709,-3.76260953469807,60.8120898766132));
#600=CARTESIAN_POINT('',(-1.5272112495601,-3.70079328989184,60.7638070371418));
#601=CARTESIAN_POINT('',(-1.84705463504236,-3.55279860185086,60.6497244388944));
#602=CARTESIAN_POINT('',(-2.00675938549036,-3.46484696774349,60.582685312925));
#603=CARTESIAN_POINT('',(-2.30941782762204,-3.27092428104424,60.4378808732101));
#604=CARTESIAN_POINT('',(-2.4523620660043,-3.16494314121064,60.3601095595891));
#605=CARTESIAN_POINT('',(-2.7485304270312,-2.91387626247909,60.18107021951));
#606=CARTESIAN_POINT('',(-2.89780217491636,-2.76523277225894,60.0782628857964));
#607=CARTESIAN_POINT('',(-3.17076769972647,-2.44748819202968,59.8698475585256));
#608=CARTESIAN_POINT('',(-3.29442988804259,-2.27836224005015,59.7642362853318));
#609=CARTESIAN_POINT('',(-3.50457057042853,-1.9375596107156,59.5688263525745));
#610=CARTESIAN_POINT('',(-3.59348348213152,-1.76769812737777,59.4784844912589));
#611=CARTESIAN_POINT('',(-3.74778213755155,-1.41126705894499,59.311642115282));
#612=CARTESIAN_POINT('',(-3.81321930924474,-1.22473512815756,59.2351115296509));
#613=CARTESIAN_POINT('',(-3.90124400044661,-0.894416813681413,59.1278761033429));
#614=CARTESIAN_POINT('',(-3.93080589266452,-0.754774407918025,59.0903120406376));
#615=CARTESIAN_POINT('',(-3.97493954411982,-0.469639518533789,59.0333460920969));
#616=CARTESIAN_POINT('',(-3.98954472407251,-0.324160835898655,59.0139037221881));
#617=CARTESIAN_POINT('',(-4.00259995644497,-0.0302735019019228,58.9965558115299));
#618=CARTESIAN_POINT('',(-4.00095637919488,0.118147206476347,58.9987750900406));
#619=CARTESIAN_POINT('',(-3.98145195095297,0.41209561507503,59.0246091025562));
#620=CARTESIAN_POINT('',(-3.96356821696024,0.557618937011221,59.0482540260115));
#621=CARTESIAN_POINT('',(-3.90662980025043,0.878121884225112,59.1210302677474));
#622=CARTESIAN_POINT('',(-3.86334682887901,1.05117767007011,59.1751148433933));
#623=CARTESIAN_POINT('',(-3.7568227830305,1.38460065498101,59.3004557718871));
#624=CARTESIAN_POINT('',(-3.69352220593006,1.54492821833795,59.3717631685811));
#625=CARTESIAN_POINT('',(-3.56873529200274,1.81092552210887,59.5028557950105));
#626=CARTESIAN_POINT('',(-3.5113936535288,1.91964530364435,59.5605370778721));
#627=CARTESIAN_POINT('',(-3.38766369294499,2.13041737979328,59.6784550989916));
#628=CARTESIAN_POINT('',(-3.32127165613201,2.23246691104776,59.7386928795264));
#629=CARTESIAN_POINT('',(-3.17963685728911,2.42995611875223,59.859872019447));
#630=CARTESIAN_POINT('',(-3.10438543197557,2.52538917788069,59.9208140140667));
#631=CARTESIAN_POINT('',(-2.9452042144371,2.70934721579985,60.0417524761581));
#632=CARTESIAN_POINT('',(-2.86127578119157,2.79787327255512,60.1017490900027));
#633=CARTESIAN_POINT('',(-2.68353213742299,2.96885093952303,60.220216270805));
#634=CARTESIAN_POINT('',(-2.5895923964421,3.05119722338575,60.2786526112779));
#635=CARTESIAN_POINT('',(-2.39294409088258,3.2077427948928,60.3916605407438));
#636=CARTESIAN_POINT('',(-2.29023415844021,3.28194080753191,60.4462315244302));
#637=CARTESIAN_POINT('',(-2.07659269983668,3.42110502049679,60.5499245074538));
#638=CARTESIAN_POINT('',(-1.96568453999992,3.48609602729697,60.5990610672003));
#639=CARTESIAN_POINT('',(-1.73599312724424,3.60598282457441,60.6905881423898));
#640=CARTESIAN_POINT('',(-1.61721438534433,3.66088433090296,60.7329824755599));
#641=CARTESIAN_POINT('',(-1.32913962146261,3.77693416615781,60.8232205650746));
#642=CARTESIAN_POINT('',(-1.15683679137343,3.83342216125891,60.8676870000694));
#643=CARTESIAN_POINT('',(-0.802710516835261,3.92287685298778,60.9384424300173));
#644=CARTESIAN_POINT('',(-0.620894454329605,3.95586150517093,60.9647453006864));
#645=CARTESIAN_POINT('',(-0.251928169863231,3.99638225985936,60.9970909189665));
#646=CARTESIAN_POINT('',(-0.0647609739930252,4.00382550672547,61.0030597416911));
#647=CARTESIAN_POINT('',(0.308260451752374,3.99246788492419,60.9939752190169));
#648=CARTESIAN_POINT('',(0.494114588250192,3.97366516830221,60.9789203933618));
#649=CARTESIAN_POINT('',(0.848969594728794,3.91279269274,60.9304799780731));
#650=CARTESIAN_POINT('',(1.01834018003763,3.87202131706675,60.8981180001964));
#651=CARTESIAN_POINT('',(1.34704122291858,3.7702931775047,60.8181040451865));
#652=CARTESIAN_POINT('',(1.50636906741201,3.70933118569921,60.7704481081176));
#653=CARTESIAN_POINT('',(1.82676698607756,3.56325105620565,60.6577242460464));
#654=CARTESIAN_POINT('',(1.98661951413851,3.47641294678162,60.5914487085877));
#655=CARTESIAN_POINT('',(2.28972858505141,3.2847146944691,60.4480671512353));
#656=CARTESIAN_POINT('',(2.43297624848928,3.17984498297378,60.3709553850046));
#657=CARTESIAN_POINT('',(2.72976152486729,2.931410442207,60.1933405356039));
#658=CARTESIAN_POINT('',(2.87940400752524,2.78431890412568,60.0912802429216));
#659=CARTESIAN_POINT('',(3.15339914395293,2.46975440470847,59.8840119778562));
#660=CARTESIAN_POINT('',(3.2777199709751,2.30225621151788,59.7788002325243));
#661=CARTESIAN_POINT('',(3.43993958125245,2.0435346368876,59.6292798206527));
#662=CARTESIAN_POINT('',(3.488247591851,1.95998002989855,59.5827706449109));
#663=CARTESIAN_POINT('',(3.57912761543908,1.78864740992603,59.4919878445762));
#664=CARTESIAN_POINT('',(3.62169886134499,1.70086883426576,59.4477145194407));
#665=CARTESIAN_POINT('',(3.74029659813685,1.43132131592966,59.3201698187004));
#666=CARTESIAN_POINT('',(3.80747088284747,1.24292483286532,59.2419209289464));
#667=CARTESIAN_POINT('',(3.89828691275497,0.907661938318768,59.1316045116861));
#668=CARTESIAN_POINT('',(3.92892882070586,0.76501053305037,59.0927231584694));
#669=CARTESIAN_POINT('',(3.96316402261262,0.546591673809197,59.0485509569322));
#670=CARTESIAN_POINT('',(3.97261660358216,0.473140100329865,59.0361918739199));
#671=CARTESIAN_POINT('',(3.98745340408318,0.325161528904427,59.016682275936));
#672=CARTESIAN_POINT('',(3.99284047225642,0.250635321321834,59.0095281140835));
#673=CARTESIAN_POINT('',(3.99741959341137,0.146618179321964,59.003437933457));
#674=CARTESIAN_POINT('',(3.99838660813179,0.11732119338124,59.0021501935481));
#675=CARTESIAN_POINT('',(3.99967703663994,0.058684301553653,59.0004307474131));
#676=CARTESIAN_POINT('',(4.00000036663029,0.0293443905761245,58.9999991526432));
#677=CARTESIAN_POINT('',(4.,0.,59.));
#678=B_SPLINE_CURVE_WITH_KNOTS('',3,(#566,#567,#568,#569,#570,#571,#572,#573,#574,#575,#576,
#577,#578,#579,#580,#581,#582,#583,#584,#585,#586,#587,#588,#589,#590,#591,#592,#593,#594,#595,
#596,#597,#598,#599,#600,#601,#602,#603,#604,#605,#606,#607,#608,#609,#610,#611,#612,#613,#614,
#615,#616,#617,#618,#619,#620,#621,#622,#623,#624,#625,#626,#627,#628,#629,#630,#631,#632,#633,
#634,#635,#636,#637,#638,#639,#640,#641,#642,#643,#644,#645,#646,#647,#648,#649,#650,#651,#652,
#653,#654,#655,#656,#657,#658,#659,#660,#661,#662,#663,#664,#665,#666,#667,#668,#669,#670,#671,
#672,#673,#674,#675,#676,#677),.UNSPECIFIED.,.T.,.F.,(4,2,2,2,2,2,2,2,2,2,2,2,2,2,2,2,2,2,2,2,2,
2,2,2,2,2,2,2,2,2,2,2,2,2,2,2,2,2,2,2,2,2,2,2,2,2,2,2,2,2,2,2,2,2,2,4),(0.,0.225303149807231,
0.450759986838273,0.902589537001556,1.51190711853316,2.12295426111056,2.53921883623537,
2.95563320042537,3.37161619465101,3.78765413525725,4.45477512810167,5.12085162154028,
5.67923095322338,6.23730451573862,6.79730186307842,7.35732512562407,7.88682741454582,
8.41646338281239,8.99711927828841,9.57810111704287,10.2788135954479,10.9803852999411,
11.6143729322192,12.2469630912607,12.6881435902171,13.1283361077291,13.5710666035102,
14.0144218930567,14.5705602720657,15.1283675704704,15.5352238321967,15.942247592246,
16.3496727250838,16.7570341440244,17.1702378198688,17.5835060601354,17.9956387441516,
18.4075372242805,18.9651425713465,19.5223214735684,20.0815238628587,20.6407656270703,
21.1700928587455,21.6995572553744,22.2782911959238,22.8573331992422,23.5548944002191,
24.2533270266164,24.5745079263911,24.8957317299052,25.5365329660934,25.9876445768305,
26.2126360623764,26.4374697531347,26.5254777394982,26.6134971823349),.UNSPECIFIED.);
#679=CARTESIAN_POINT('',(4.,0.,59.));
#680=VERTEX_POINT('',#679);
#681=EDGE_CURVE('E177',#680,#680,#678,.T.);
#682=ORIENTED_EDGE('',*,*,#681,.T.);
#683=EDGE_LOOP('',(#682));
#684=FACE_BOUND('',#683,.T.);
#685=ORIENTED_EDGE('',*,*,#558,.T.);
#686=EDGE_LOOP('',(#685));
#687=FACE_BOUND('',#686,.T.);
#688=ADVANCED_FACE('F170',(#684,#687),#65,.F.);
#689=CARTESIAN_POINT('',(0.,-8.,56.));
#690=DIRECTION('',(0.,1.,0.));
#691=DIRECTION('',(0.,0.,1.));
#692=AXIS2_PLACEMENT_3D('',#689,#690,#691);
#693=CYLINDRICAL_SURFACE('',#692,5.);
#694=ORIENTED_EDGE('',*,*,#181,.F.);
#695=EDGE_LOOP('',(#694));
#696=FACE_BOUND('',#695,.T.);
#697=CARTESIAN_POINT('',(0.,-8.,56.));
#698=DIRECTION('',(0.,1.,0.));
#699=DIRECTION('',(0.,0.,1.));
#700=AXIS2_PLACEMENT_3D('',#697,#698,#699);
#701=CIRCLE('',#700,5.);
#702=CARTESIAN_POINT('',(0.,-8.,61.));
#703=VERTEX_POINT('',#702);
#704=EDGE_CURVE('E152',#703,#703,#701,.T.);
#705=ORIENTED_EDGE('',*,*,#704,.F.);
#706=EDGE_LOOP('',(#705));
#707=FACE_BOUND('',#706,.T.);
#708=ORIENTED_EDGE('',*,*,#681,.F.);
#709=EDGE_LOOP('',(#708));
#710=FACE_BOUND('',#709,.T.);
#711=ORIENTED_EDGE('',*,*,#420,.F.);
#712=EDGE_LOOP('',(#711));
#713=FACE_BOUND('',#712,.T.);
#714=ADVANCED_FACE('F165',(#696,#707,#710,#713),#693,.F.);
#715=CARTESIAN_POINT('',(0.,-8.,56.));
#716=DIRECTION('',(0.,1.,0.));
#717=DIRECTION('',(0.,0.,1.));
#718=AXIS2_PLACEMENT_3D('',#715,#716,#717);
#719=PLANE('',#718);
#720=CARTESIAN_POINT('',(0.,-8.,56.));
#721=DIRECTION('',(0.,1.,0.));
#722=DIRECTION('',(0.,0.,1.));
#723=AXIS2_PLACEMENT_3D('',#720,#721,#722);
#724=CIRCLE('',#723,3.);
#725=CARTESIAN_POINT('',(0.,-8.,59.));
#726=VERTEX_POINT('',#725);
#727=EDGE_CURVE('E143',#726,#726,#724,.T.);
#728=ORIENTED_EDGE('',*,*,#727,.F.);
#729=EDGE_LOOP('',(#728));
#730=FACE_BOUND('',#729,.T.);
#731=ORIENTED_EDGE('',*,*,#704,.T.);
#732=EDGE_LOOP('',(#731));
#733=FACE_BOUND('',#732,.T.);
#734=ADVANCED_FACE('F160',(#730,#733),#719,.T.);
#735=CARTESIAN_POINT('',(0.,-12.5,56.));
#736=DIRECTION('',(0.,1.,0.));
#737=DIRECTION('',(0.,0.,1.));
#738=AXIS2_PLACEMENT_3D('',#735,#736,#737);
#739=CYLINDRICAL_SURFACE('',#738,3.);
#740=ORIENTED_EDGE('',*,*,#727,.T.);
#741=EDGE_LOOP('',(#740));
#742=FACE_BOUND('',#741,.T.);
#743=ORIENTED_EDGE('',*,*,#283,.F.);
#744=EDGE_LOOP('',(#743));
#745=FACE_BOUND('',#744,.T.);
#746=ADVANCED_FACE('F154',(#742,#745),#739,.F.);
#747=CARTESIAN_POINT('',(-12.5,0.,71.));
#748=DIRECTION('',(0.,0.,-1.));
#749=DIRECTION('',(0.,1.,0.));
#750=AXIS2_PLACEMENT_3D('',#747,#748,#749);
#751=PLANE('',#750);
#752=DIRECTION('',(1.,0.,0.));
#753=VECTOR('',#752,1.);
#754=CARTESIAN_POINT('',(-12.5,0.,71.));
#755=LINE('',#754,#753);
#756=EDGE_CURVE('E127',#440,#518,#755,.T.);
#757=ORIENTED_EDGE('',*,*,#756,.T.);
#758=ORIENTED_EDGE('',*,*,#541,.F.);
#759=DIRECTION('',(0.,1.,0.));
#760=VECTOR('',#759,1.);
#761=CARTESIAN_POINT('',(0.,0.,71.));
#762=LINE('',#761,#760);
#763=EDGE_CURVE('E120',#533,#449,#762,.T.);
#764=ORIENTED_EDGE('',*,*,#763,.T.);
#765=ORIENTED_EDGE('',*,*,#450,.F.);
#766=EDGE_LOOP('',(#757,#758,#764,#765));
#767=FACE_BOUND('',#766,.T.);
#768=ADVANCED_FACE('F159',(#767),#751,.F.);
#769=CARTESIAN_POINT('',(0.,0.,71.));
#770=DIRECTION('',(1.,0.,0.));
#771=DIRECTION('',(0.,0.,-1.));
#772=AXIS2_PLACEMENT_3D('',#769,#770,#771);
#773=PLANE('',#772);
#774=ORIENTED_EDGE('',*,*,#763,.F.);
#775=ORIENTED_EDGE('',*,*,#534,.F.);
#776=DIRECTION('',(0.,0.,-1.));
#777=VECTOR('',#776,1.);
#778=CARTESIAN_POINT('',(0.,10.,-6.2769861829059));
#779=LINE('',#778,#777);
#780=EDGE_CURVE('E64',#529,#31,#779,.F.);
#781=ORIENTED_EDGE('',*,*,#780,.T.);
#782=ORIENTED_EDGE('',*,*,#32,.F.);
#783=ORIENTED_EDGE('',*,*,#488,.T.);
#784=ORIENTED_EDGE('',*,*,#456,.F.);
#785=EDGE_LOOP('',(#774,#775,#781,#782,#783,#784));
#786=FACE_BOUND('',#785,.T.);
#787=ADVANCED_FACE('F312',(#786),#773,.F.);
#788=CARTESIAN_POINT('',(-12.5,0.,71.));
#789=DIRECTION('',(0.,-1.,0.));
#790=DIRECTION('',(0.,0.,-1.));
#791=AXIS2_PLACEMENT_3D('',#788,#789,#790);
#792=PLANE('',#791);
#793=ORIENTED_EDGE('',*,*,#481,.T.);
#794=ORIENTED_EDGE('',*,*,#49,.F.);
#795=EDGE_CURVE('E50',#520,#40,#46,.T.);
#796=ORIENTED_EDGE('',*,*,#795,.F.);
#797=ORIENTED_EDGE('',*,*,#521,.F.);
#798=ORIENTED_EDGE('',*,*,#756,.F.);
#799=ORIENTED_EDGE('',*,*,#441,.F.);
#800=EDGE_LOOP('',(#793,#794,#796,#797,#798,#799));
#801=FACE_BOUND('',#800,.T.);
#802=ADVANCED_FACE('F97',(#801),#792,.F.);
#803=CARTESIAN_POINT('',(0.,0.,-6.2769861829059));
#804=DIRECTION('',(0.,0.,-1.));
#805=DIRECTION('',(-1.,0.,0.));
#806=AXIS2_PLACEMENT_3D('',#803,#804,#805);
#807=CYLINDRICAL_SURFACE('',#806,10.);
#808=ORIENTED_EDGE('',*,*,#780,.F.);
#809=EDGE_CURVE('E118',#520,#529,#527,.T.);
#810=ORIENTED_EDGE('',*,*,#809,.F.);
#811=ORIENTED_EDGE('',*,*,#795,.T.);
#812=EDGE_CURVE('E111',#40,#31,#38,.T.);
#813=ORIENTED_EDGE('',*,*,#812,.T.);
#814=EDGE_LOOP('',(#808,#810,#811,#813));
#815=FACE_BOUND('',#814,.T.);
#816=ADVANCED_FACE('F116',(#815),#807,.T.);
#817=CARTESIAN_POINT('',(0.,10.,120.));
#818=DIRECTION('',(0.,0.,1.));
#819=DIRECTION('',(1.,0.,0.));
#820=AXIS2_PLACEMENT_3D('',#817,#818,#819);
#821=PLANE('',#820);
#822=CARTESIAN_POINT('',(0.,0.,120.));
#823=DIRECTION('',(0.,0.,-1.));
#824=DIRECTION('',(-1.,0.,0.));
#825=AXIS2_PLACEMENT_3D('',#822,#823,#824);
#826=CIRCLE('',#825,7.99999999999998);
#827=CARTESIAN_POINT('',(-7.99999999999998,0.,120.));
#828=VERTEX_POINT('',#827);
#829=EDGE_CURVE('E112',#828,#828,#826,.T.);
#830=ORIENTED_EDGE('',*,*,#829,.T.);
#831=EDGE_LOOP('',(#830));
#832=FACE_BOUND('',#831,.T.);
#833=ORIENTED_EDGE('',*,*,#812,.F.);
#834=ORIENTED_EDGE('',*,*,#41,.F.);
#835=EDGE_LOOP('',(#833,#834));
#836=FACE_BOUND('',#835,.T.);
#837=ADVANCED_FACE('F119',(#832,#836),#821,.T.);
#838=CARTESIAN_POINT('',(0.,0.,-6.2769861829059));
#839=DIRECTION('',(0.,0.,-1.));
#840=DIRECTION('',(-1.,0.,0.));
#841=AXIS2_PLACEMENT_3D('',#838,#839,#840);
#842=CYLINDRICAL_SURFACE('',#841,7.99999999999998);
#843=CARTESIAN_POINT('',(0.,0.,118.5));
#844=DIRECTION('',(0.,0.,-1.));
#845=DIRECTION('',(-1.,0.,0.));
#846=AXIS2_PLACEMENT_3D('',#843,#844,#845);
#847=CIRCLE('',#846,7.99999999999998);
#848=CARTESIAN_POINT('',(-7.99999999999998,0.,118.5));
#849=VERTEX_POINT('',#848);
#850=EDGE_CURVE('E409',#849,#849,#847,.T.);
#851=ORIENTED_EDGE('',*,*,#850,.T.);
#852=EDGE_LOOP('',(#851));
#853=FACE_BOUND('',#852,.T.);
#854=ORIENTED_EDGE('',*,*,#829,.F.);
#855=EDGE_LOOP('',(#854));
#856=FACE_BOUND('',#855,.T.);
#857=ADVANCED_FACE('F283',(#853,#856),#842,.F.);
#858=CARTESIAN_POINT('',(0.,7.99999999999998,118.5));
#859=DIRECTION('',(0.,0.,-1.));
#860=DIRECTION('',(-1.,0.,0.));
#861=AXIS2_PLACEMENT_3D('',#858,#859,#860);
#862=PLANE('',#861);
#863=ORIENTED_EDGE('',*,*,#809,.T.);
#864=ORIENTED_EDGE('',*,*,#530,.T.);
#865=EDGE_LOOP('',(#863,#864));
#866=FACE_BOUND('',#865,.T.);
#867=ORIENTED_EDGE('',*,*,#850,.F.);
#868=EDGE_LOOP('',(#867));
#869=FACE_BOUND('',#868,.T.);
#870=ADVANCED_FACE('F273',(#866,#869),#862,.T.);
#871=CLOSED_SHELL('',(#60,#196,#471,#493,#505,#545,#565,#688,#714,#734,#746,#768,#787,#802,#816,
#837,#857,#870));
#872=MANIFOLD_SOLID_BREP('B2',#871);
#873=ADVANCED_BREP_SHAPE_REPRESENTATION('',(#18,#872),#14);
#874=SHAPE_DEFINITION_REPRESENTATION(#9,#873);
ENDSEC;
END-ISO-10303-21;
